VERSION 5.7 ;
  NOWIREEXTENSIONATPIN ON ;
  DIVIDERCHAR "/" ;
  BUSBITCHARS "[]" ;
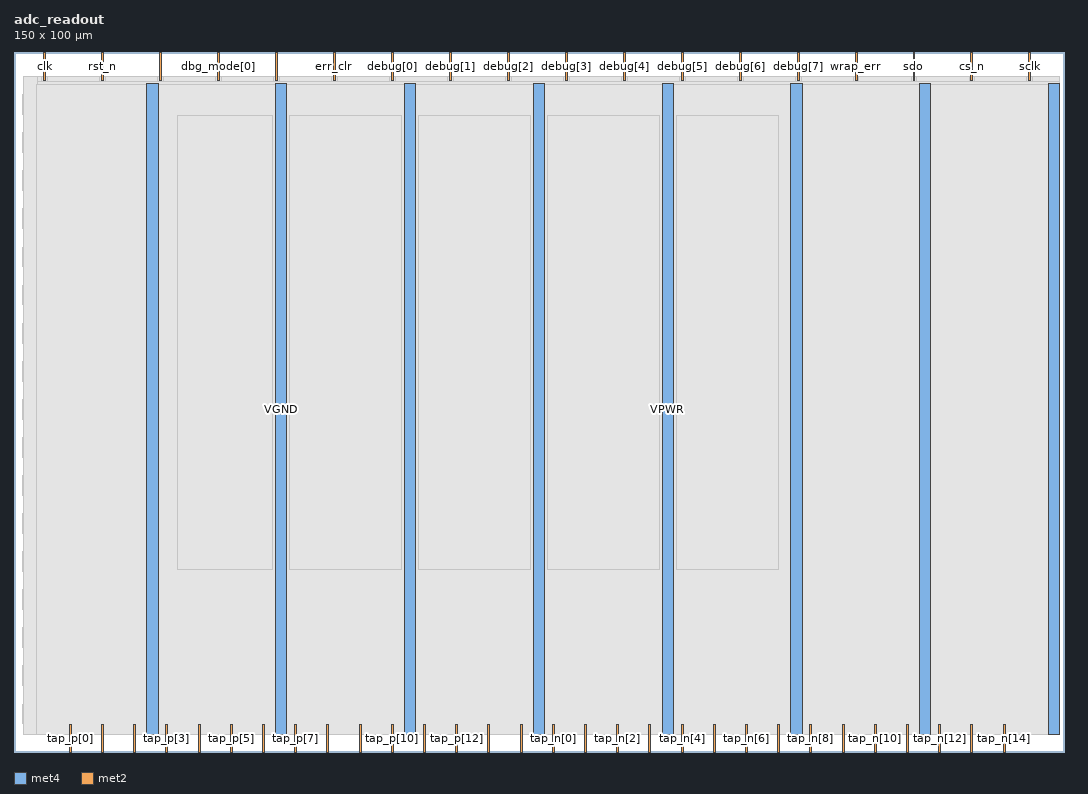
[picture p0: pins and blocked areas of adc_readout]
MACRO adc_readout
  CLASS BLOCK ;
  FOREIGN adc_readout ;
  ORIGIN 0.000 0.000 ;
  SIZE 150.000 BY 100.000 ;
  PIN VGND
    DIRECTION INOUT ;
    USE GROUND ;
    PORT
      LAYER met4 ;
        RECT 37.380 2.480 38.980 95.440 ;
    END
    PORT
      LAYER met4 ;
        RECT 74.180 2.480 75.780 95.440 ;
    END
    PORT
      LAYER met4 ;
        RECT 110.980 2.480 112.580 95.440 ;
    END
    PORT
      LAYER met4 ;
        RECT 147.780 2.480 149.380 95.440 ;
    END
  END VGND
  PIN VPWR
    DIRECTION INOUT ;
    USE POWER ;
    PORT
      LAYER met4 ;
        RECT 18.980 2.480 20.580 95.440 ;
    END
    PORT
      LAYER met4 ;
        RECT 55.780 2.480 57.380 95.440 ;
    END
    PORT
      LAYER met4 ;
        RECT 92.580 2.480 94.180 95.440 ;
    END
    PORT
      LAYER met4 ;
        RECT 129.380 2.480 130.980 95.440 ;
    END
  END VPWR
  PIN clk
    DIRECTION INPUT ;
    USE SIGNAL ;
    ANTENNAGATEAREA 0.647700 ;
    ANTENNADIFFAREA 0.434700 ;
    PORT
      LAYER met2 ;
        RECT 4.230 96.000 4.510 100.000 ;
    END
  END clk
  PIN cs_n
    DIRECTION OUTPUT TRISTATE ;
    USE SIGNAL ;
    ANTENNADIFFAREA 0.429000 ;
    PORT
      LAYER met2 ;
        RECT 136.710 96.000 136.990 100.000 ;
    END
  END cs_n
  PIN dbg_mode[0]
    DIRECTION INPUT ;
    USE SIGNAL ;
    ANTENNAGATEAREA 1.364400 ;
    ANTENNADIFFAREA 0.869400 ;
    PORT
      LAYER met2 ;
        RECT 29.070 96.000 29.350 100.000 ;
    END
  END dbg_mode[0]
  PIN dbg_mode[1]
    DIRECTION INPUT ;
    USE SIGNAL ;
    ANTENNAGATEAREA 1.803600 ;
    ANTENNADIFFAREA 1.304100 ;
    PORT
      LAYER met2 ;
        RECT 37.350 96.000 37.630 100.000 ;
    END
  END dbg_mode[1]
  PIN debug[0]
    DIRECTION OUTPUT TRISTATE ;
    USE SIGNAL ;
    ANTENNADIFFAREA 0.429000 ;
    PORT
      LAYER met2 ;
        RECT 53.910 96.000 54.190 100.000 ;
    END
  END debug[0]
  PIN debug[1]
    DIRECTION OUTPUT TRISTATE ;
    USE SIGNAL ;
    ANTENNADIFFAREA 0.445500 ;
    PORT
      LAYER met2 ;
        RECT 62.190 96.000 62.470 100.000 ;
    END
  END debug[1]
  PIN debug[2]
    DIRECTION OUTPUT TRISTATE ;
    USE SIGNAL ;
    ANTENNADIFFAREA 0.657000 ;
    PORT
      LAYER met2 ;
        RECT 70.470 96.000 70.750 100.000 ;
    END
  END debug[2]
  PIN debug[3]
    DIRECTION OUTPUT TRISTATE ;
    USE SIGNAL ;
    ANTENNADIFFAREA 0.621000 ;
    PORT
      LAYER met2 ;
        RECT 78.750 96.000 79.030 100.000 ;
    END
  END debug[3]
  PIN debug[4]
    DIRECTION OUTPUT TRISTATE ;
    USE SIGNAL ;
    ANTENNADIFFAREA 0.657000 ;
    PORT
      LAYER met2 ;
        RECT 87.030 96.000 87.310 100.000 ;
    END
  END debug[4]
  PIN debug[5]
    DIRECTION OUTPUT TRISTATE ;
    USE SIGNAL ;
    ANTENNADIFFAREA 0.621000 ;
    PORT
      LAYER met2 ;
        RECT 95.310 96.000 95.590 100.000 ;
    END
  END debug[5]
  PIN debug[6]
    DIRECTION OUTPUT TRISTATE ;
    USE SIGNAL ;
    ANTENNADIFFAREA 0.621000 ;
    PORT
      LAYER met2 ;
        RECT 103.590 96.000 103.870 100.000 ;
    END
  END debug[6]
  PIN debug[7]
    DIRECTION OUTPUT TRISTATE ;
    USE SIGNAL ;
    ANTENNADIFFAREA 0.643500 ;
    PORT
      LAYER met2 ;
        RECT 111.870 96.000 112.150 100.000 ;
    END
  END debug[7]
  PIN err_clr
    DIRECTION INPUT ;
    USE SIGNAL ;
    ANTENNAGATEAREA 0.560700 ;
    ANTENNADIFFAREA 0.434700 ;
    PORT
      LAYER met2 ;
        RECT 45.630 96.000 45.910 100.000 ;
    END
  END err_clr
  PIN osr_sel
    DIRECTION INPUT ;
    USE SIGNAL ;
    ANTENNAGATEAREA 0.560700 ;
    ANTENNADIFFAREA 0.434700 ;
    PORT
      LAYER met2 ;
        RECT 20.790 96.000 21.070 100.000 ;
    END
  END osr_sel
  PIN rst_n
    DIRECTION INPUT ;
    USE SIGNAL ;
    ANTENNAGATEAREA 9.613800 ;
    ANTENNADIFFAREA 6.085800 ;
    PORT
      LAYER met2 ;
        RECT 12.510 96.000 12.790 100.000 ;
    END
  END rst_n
  PIN sclk
    DIRECTION OUTPUT TRISTATE ;
    USE SIGNAL ;
    ANTENNADIFFAREA 0.445500 ;
    PORT
      LAYER met2 ;
        RECT 144.990 96.000 145.270 100.000 ;
    END
  END sclk
  PIN sdo
    DIRECTION OUTPUT TRISTATE ;
    USE SIGNAL ;
    ANTENNAGATEAREA 0.247500 ;
    ANTENNADIFFAREA 0.445500 ;
    PORT
      LAYER met2 ;
        RECT 128.430 96.000 128.710 100.000 ;
    END
  END sdo
  PIN tap_n[0]
    DIRECTION INPUT ;
    USE SIGNAL ;
    ANTENNAGATEAREA 0.647700 ;
    ANTENNADIFFAREA 0.434700 ;
    PORT
      LAYER met2 ;
        RECT 76.910 0.000 77.190 4.000 ;
    END
  END tap_n[0]
  PIN tap_n[10]
    DIRECTION INPUT ;
    USE SIGNAL ;
    ANTENNAGATEAREA 0.560700 ;
    ANTENNADIFFAREA 0.434700 ;
    PORT
      LAYER met2 ;
        RECT 122.910 0.000 123.190 4.000 ;
    END
  END tap_n[10]
  PIN tap_n[11]
    DIRECTION INPUT ;
    USE SIGNAL ;
    ANTENNAGATEAREA 0.560700 ;
    ANTENNADIFFAREA 0.434700 ;
    PORT
      LAYER met2 ;
        RECT 127.510 0.000 127.790 4.000 ;
    END
  END tap_n[11]
  PIN tap_n[12]
    DIRECTION INPUT ;
    USE SIGNAL ;
    ANTENNAGATEAREA 0.560700 ;
    ANTENNADIFFAREA 0.434700 ;
    PORT
      LAYER met2 ;
        RECT 132.110 0.000 132.390 4.000 ;
    END
  END tap_n[12]
  PIN tap_n[13]
    DIRECTION INPUT ;
    USE SIGNAL ;
    ANTENNAGATEAREA 0.560700 ;
    ANTENNADIFFAREA 0.434700 ;
    PORT
      LAYER met2 ;
        RECT 136.710 0.000 136.990 4.000 ;
    END
  END tap_n[13]
  PIN tap_n[14]
    DIRECTION INPUT ;
    USE SIGNAL ;
    ANTENNAGATEAREA 0.560700 ;
    ANTENNADIFFAREA 0.434700 ;
    PORT
      LAYER met2 ;
        RECT 141.310 0.000 141.590 4.000 ;
    END
  END tap_n[14]
  PIN tap_n[1]
    DIRECTION INPUT ;
    USE SIGNAL ;
    ANTENNAGATEAREA 0.560700 ;
    ANTENNADIFFAREA 0.434700 ;
    PORT
      LAYER met2 ;
        RECT 81.510 0.000 81.790 4.000 ;
    END
  END tap_n[1]
  PIN tap_n[2]
    DIRECTION INPUT ;
    USE SIGNAL ;
    ANTENNAGATEAREA 0.560700 ;
    ANTENNADIFFAREA 0.434700 ;
    PORT
      LAYER met2 ;
        RECT 86.110 0.000 86.390 4.000 ;
    END
  END tap_n[2]
  PIN tap_n[3]
    DIRECTION INPUT ;
    USE SIGNAL ;
    ANTENNAGATEAREA 0.560700 ;
    ANTENNADIFFAREA 0.434700 ;
    PORT
      LAYER met2 ;
        RECT 90.710 0.000 90.990 4.000 ;
    END
  END tap_n[3]
  PIN tap_n[4]
    DIRECTION INPUT ;
    USE SIGNAL ;
    ANTENNAGATEAREA 0.560700 ;
    ANTENNADIFFAREA 0.434700 ;
    PORT
      LAYER met2 ;
        RECT 95.310 0.000 95.590 4.000 ;
    END
  END tap_n[4]
  PIN tap_n[5]
    DIRECTION INPUT ;
    USE SIGNAL ;
    ANTENNAGATEAREA 0.560700 ;
    ANTENNADIFFAREA 0.434700 ;
    PORT
      LAYER met2 ;
        RECT 99.910 0.000 100.190 4.000 ;
    END
  END tap_n[5]
  PIN tap_n[6]
    DIRECTION INPUT ;
    USE SIGNAL ;
    ANTENNAGATEAREA 0.560700 ;
    ANTENNADIFFAREA 0.434700 ;
    PORT
      LAYER met2 ;
        RECT 104.510 0.000 104.790 4.000 ;
    END
  END tap_n[6]
  PIN tap_n[7]
    DIRECTION INPUT ;
    USE SIGNAL ;
    ANTENNAGATEAREA 0.560700 ;
    ANTENNADIFFAREA 0.434700 ;
    PORT
      LAYER met2 ;
        RECT 109.110 0.000 109.390 4.000 ;
    END
  END tap_n[7]
  PIN tap_n[8]
    DIRECTION INPUT ;
    USE SIGNAL ;
    ANTENNAGATEAREA 0.560700 ;
    ANTENNADIFFAREA 0.434700 ;
    PORT
      LAYER met2 ;
        RECT 113.710 0.000 113.990 4.000 ;
    END
  END tap_n[8]
  PIN tap_n[9]
    DIRECTION INPUT ;
    USE SIGNAL ;
    ANTENNAGATEAREA 0.560700 ;
    ANTENNADIFFAREA 0.434700 ;
    PORT
      LAYER met2 ;
        RECT 118.310 0.000 118.590 4.000 ;
    END
  END tap_n[9]
  PIN tap_p[0]
    DIRECTION INPUT ;
    USE SIGNAL ;
    ANTENNAGATEAREA 0.647700 ;
    ANTENNADIFFAREA 0.434700 ;
    PORT
      LAYER met2 ;
        RECT 7.910 0.000 8.190 4.000 ;
    END
  END tap_p[0]
  PIN tap_p[10]
    DIRECTION INPUT ;
    USE SIGNAL ;
    ANTENNAGATEAREA 0.560700 ;
    ANTENNADIFFAREA 0.434700 ;
    PORT
      LAYER met2 ;
        RECT 53.910 0.000 54.190 4.000 ;
    END
  END tap_p[10]
  PIN tap_p[11]
    DIRECTION INPUT ;
    USE SIGNAL ;
    ANTENNAGATEAREA 0.560700 ;
    ANTENNADIFFAREA 0.434700 ;
    PORT
      LAYER met2 ;
        RECT 58.510 0.000 58.790 4.000 ;
    END
  END tap_p[11]
  PIN tap_p[12]
    DIRECTION INPUT ;
    USE SIGNAL ;
    ANTENNAGATEAREA 0.560700 ;
    ANTENNADIFFAREA 0.434700 ;
    PORT
      LAYER met2 ;
        RECT 63.110 0.000 63.390 4.000 ;
    END
  END tap_p[12]
  PIN tap_p[13]
    DIRECTION INPUT ;
    USE SIGNAL ;
    ANTENNAGATEAREA 0.560700 ;
    ANTENNADIFFAREA 0.434700 ;
    PORT
      LAYER met2 ;
        RECT 67.710 0.000 67.990 4.000 ;
    END
  END tap_p[13]
  PIN tap_p[14]
    DIRECTION INPUT ;
    USE SIGNAL ;
    ANTENNAGATEAREA 0.560700 ;
    ANTENNADIFFAREA 0.434700 ;
    PORT
      LAYER met2 ;
        RECT 72.310 0.000 72.590 4.000 ;
    END
  END tap_p[14]
  PIN tap_p[1]
    DIRECTION INPUT ;
    USE SIGNAL ;
    ANTENNAGATEAREA 0.560700 ;
    ANTENNADIFFAREA 0.434700 ;
    PORT
      LAYER met2 ;
        RECT 12.510 0.000 12.790 4.000 ;
    END
  END tap_p[1]
  PIN tap_p[2]
    DIRECTION INPUT ;
    USE SIGNAL ;
    ANTENNAGATEAREA 0.560700 ;
    ANTENNADIFFAREA 0.434700 ;
    PORT
      LAYER met2 ;
        RECT 17.110 0.000 17.390 4.000 ;
    END
  END tap_p[2]
  PIN tap_p[3]
    DIRECTION INPUT ;
    USE SIGNAL ;
    ANTENNAGATEAREA 0.560700 ;
    ANTENNADIFFAREA 0.434700 ;
    PORT
      LAYER met2 ;
        RECT 21.710 0.000 21.990 4.000 ;
    END
  END tap_p[3]
  PIN tap_p[4]
    DIRECTION INPUT ;
    USE SIGNAL ;
    ANTENNAGATEAREA 0.560700 ;
    ANTENNADIFFAREA 0.434700 ;
    PORT
      LAYER met2 ;
        RECT 26.310 0.000 26.590 4.000 ;
    END
  END tap_p[4]
  PIN tap_p[5]
    DIRECTION INPUT ;
    USE SIGNAL ;
    ANTENNAGATEAREA 0.560700 ;
    ANTENNADIFFAREA 0.434700 ;
    PORT
      LAYER met2 ;
        RECT 30.910 0.000 31.190 4.000 ;
    END
  END tap_p[5]
  PIN tap_p[6]
    DIRECTION INPUT ;
    USE SIGNAL ;
    ANTENNAGATEAREA 0.560700 ;
    ANTENNADIFFAREA 0.434700 ;
    PORT
      LAYER met2 ;
        RECT 35.510 0.000 35.790 4.000 ;
    END
  END tap_p[6]
  PIN tap_p[7]
    DIRECTION INPUT ;
    USE SIGNAL ;
    ANTENNAGATEAREA 0.560700 ;
    ANTENNADIFFAREA 0.434700 ;
    PORT
      LAYER met2 ;
        RECT 40.110 0.000 40.390 4.000 ;
    END
  END tap_p[7]
  PIN tap_p[8]
    DIRECTION INPUT ;
    USE SIGNAL ;
    ANTENNAGATEAREA 0.560700 ;
    ANTENNADIFFAREA 0.434700 ;
    PORT
      LAYER met2 ;
        RECT 44.710 0.000 44.990 4.000 ;
    END
  END tap_p[8]
  PIN tap_p[9]
    DIRECTION INPUT ;
    USE SIGNAL ;
    ANTENNAGATEAREA 0.560700 ;
    ANTENNADIFFAREA 0.434700 ;
    PORT
      LAYER met2 ;
        RECT 49.310 0.000 49.590 4.000 ;
    END
  END tap_p[9]
  PIN wrap_err
    DIRECTION OUTPUT TRISTATE ;
    USE SIGNAL ;
    ANTENNAGATEAREA 0.247500 ;
    ANTENNADIFFAREA 0.891000 ;
    PORT
      LAYER met2 ;
        RECT 120.150 96.000 120.430 100.000 ;
    END
  END wrap_err
  OBS
      LAYER nwell ;
        RECT 1.190 91.065 148.770 93.895 ;
        RECT 1.190 85.625 148.770 88.455 ;
        RECT 1.190 80.185 148.770 83.015 ;
        RECT 1.190 77.525 35.560 77.575 ;
        RECT 1.190 74.745 148.770 77.525 ;
        RECT 1.190 69.305 148.770 72.135 ;
        RECT 1.190 66.645 45.615 66.695 ;
        RECT 1.190 63.865 148.770 66.645 ;
        RECT 1.190 58.425 148.770 61.255 ;
        RECT 1.190 52.985 148.770 55.815 ;
        RECT 1.190 47.545 148.770 50.375 ;
        RECT 1.190 42.155 148.770 44.935 ;
        RECT 1.190 42.105 8.815 42.155 ;
        RECT 1.190 36.665 148.770 39.495 ;
        RECT 1.190 31.225 148.770 34.055 ;
        RECT 1.190 25.785 148.770 28.615 ;
        RECT 1.190 20.345 148.770 23.175 ;
        RECT 1.190 14.905 148.770 17.735 ;
        RECT 1.190 9.465 148.770 12.295 ;
        RECT 1.190 4.025 148.770 6.855 ;
      LAYER li1 ;
        RECT 1.380 2.635 148.580 95.285 ;
      LAYER met1 ;
        RECT 1.380 2.480 149.380 96.520 ;
      LAYER met2 ;
        RECT 3.310 95.720 3.950 96.550 ;
        RECT 4.790 95.720 12.230 96.550 ;
        RECT 13.070 95.720 20.510 96.550 ;
        RECT 21.350 95.720 28.790 96.550 ;
        RECT 29.630 95.720 37.070 96.550 ;
        RECT 37.910 95.720 45.350 96.550 ;
        RECT 46.190 95.720 53.630 96.550 ;
        RECT 54.470 95.720 61.910 96.550 ;
        RECT 62.750 95.720 70.190 96.550 ;
        RECT 71.030 95.720 78.470 96.550 ;
        RECT 79.310 95.720 86.750 96.550 ;
        RECT 87.590 95.720 95.030 96.550 ;
        RECT 95.870 95.720 103.310 96.550 ;
        RECT 104.150 95.720 111.590 96.550 ;
        RECT 112.430 95.720 119.870 96.550 ;
        RECT 120.710 95.720 128.150 96.550 ;
        RECT 128.990 95.720 136.430 96.550 ;
        RECT 137.270 95.720 144.710 96.550 ;
        RECT 145.550 95.720 149.350 96.550 ;
        RECT 3.310 4.280 149.350 95.720 ;
        RECT 3.310 2.535 7.630 4.280 ;
        RECT 8.470 2.535 12.230 4.280 ;
        RECT 13.070 2.535 16.830 4.280 ;
        RECT 17.670 2.535 21.430 4.280 ;
        RECT 22.270 2.535 26.030 4.280 ;
        RECT 26.870 2.535 30.630 4.280 ;
        RECT 31.470 2.535 35.230 4.280 ;
        RECT 36.070 2.535 39.830 4.280 ;
        RECT 40.670 2.535 44.430 4.280 ;
        RECT 45.270 2.535 49.030 4.280 ;
        RECT 49.870 2.535 53.630 4.280 ;
        RECT 54.470 2.535 58.230 4.280 ;
        RECT 59.070 2.535 62.830 4.280 ;
        RECT 63.670 2.535 67.430 4.280 ;
        RECT 68.270 2.535 72.030 4.280 ;
        RECT 72.870 2.535 76.630 4.280 ;
        RECT 77.470 2.535 81.230 4.280 ;
        RECT 82.070 2.535 85.830 4.280 ;
        RECT 86.670 2.535 90.430 4.280 ;
        RECT 91.270 2.535 95.030 4.280 ;
        RECT 95.870 2.535 99.630 4.280 ;
        RECT 100.470 2.535 104.230 4.280 ;
        RECT 105.070 2.535 108.830 4.280 ;
        RECT 109.670 2.535 113.430 4.280 ;
        RECT 114.270 2.535 118.030 4.280 ;
        RECT 118.870 2.535 122.630 4.280 ;
        RECT 123.470 2.535 127.230 4.280 ;
        RECT 128.070 2.535 131.830 4.280 ;
        RECT 132.670 2.535 136.430 4.280 ;
        RECT 137.270 2.535 141.030 4.280 ;
        RECT 141.870 2.535 149.350 4.280 ;
      LAYER met3 ;
        RECT 3.285 2.555 149.370 95.365 ;
      LAYER met4 ;
        RECT 23.295 26.015 36.980 90.945 ;
        RECT 39.380 26.015 55.380 90.945 ;
        RECT 57.780 26.015 73.780 90.945 ;
        RECT 76.180 26.015 92.180 90.945 ;
        RECT 94.580 26.015 109.185 90.945 ;
  END
END adc_readout
END LIBRARY

